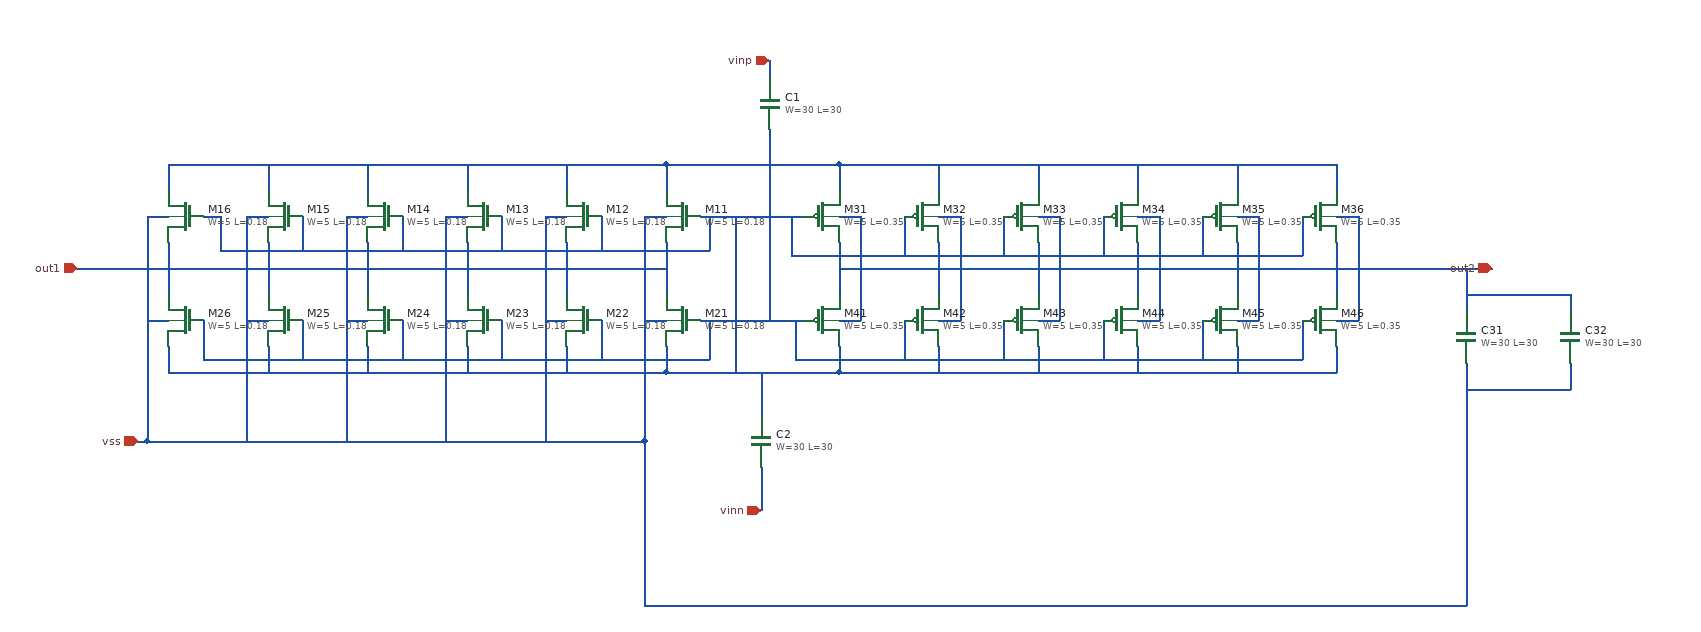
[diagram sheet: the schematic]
v {xschem version=3.1.0 file_version=1.2
}
G {}
K {}
V {}
S {}
E {}
N 765 -280 965 -280 { lab=#net1}
N 765 -520 765 -490 { lab=#net2}
N 765 -520 965 -520 { lab=#net2}
N 845 -460 845 -280 { lab=#net1}
N 885 -520 885 -340 { lab=#net2}
N 965 -520 965 -490 { lab=#net2}
N 965 -430 965 -370 { lab=out2}
N 965 -310 965 -280 { lab=#net1}
N 765 -310 765 -280 { lab=#net1}
N 805 -340 925 -340 { lab=#net2}
N 805 -460 925 -460 { lab=#net1}
N 765 -430 765 -370 { lab=vss}
N 885 -560 885 -520 {
lab=#net2}
N 875 -280 875 -230 {
lab=#net1}
N 885 -640 885 -620 {
lab=vinp}
N 875 -170 875 -120 {
lab=vinn}
N 190 -520 190 -490 {
lab=#net2}
N 190 -520 765 -520 {
lab=#net2}
N 305 -520 305 -490 {
lab=#net2}
N 420 -520 420 -490 {
lab=#net2}
N 535 -520 535 -490 {
lab=#net2}
N 650 -520 650 -490 {
lab=#net2}
N 965 -520 1540 -520 {
lab=#net2}
N 1540 -520 1540 -490 {
lab=#net2}
N 1080 -520 1080 -490 {
lab=#net2}
N 1195 -520 1195 -490 {
lab=#net2}
N 1310 -520 1310 -490 {
lab=#net2}
N 1425 -520 1425 -490 {
lab=#net2}
N 190 -280 765 -280 {
lab=#net1}
N 190 -310 190 -280 {
lab=#net1}
N 305 -310 305 -280 {
lab=#net1}
N 420 -310 420 -280 {
lab=#net1}
N 535 -310 535 -280 {
lab=#net1}
N 650 -310 650 -280 {
lab=#net1}
N 965 -280 1540 -280 {
lab=#net1}
N 1540 -310 1540 -280 {
lab=#net1}
N 1425 -310 1425 -280 {
lab=#net1}
N 1310 -310 1310 -280 {
lab=#net1}
N 1195 -310 1195 -280 {
lab=#net1}
N 1080 -310 1080 -280 {
lab=#net1}
N 190 -430 190 -370 {
lab=vss}
N 305 -430 305 -370 {
lab=vss}
N 420 -430 420 -370 {
lab=vss}
N 535 -430 535 -370 {
lab=vss}
N 650 -430 650 -370 {
lab=vss}
N 650 -400 765 -400 {
lab=vss}
N 535 -400 650 -400 {
lab=vss}
N 420 -400 535 -400 {
lab=vss}
N 305 -400 420 -400 {
lab=vss}
N 190 -400 305 -400 {
lab=vss}
N 1540 -430 1540 -370 {
lab=out2}
N 1080 -430 1080 -370 {
lab=out2}
N 1195 -430 1195 -370 {
lab=out2}
N 1310 -430 1310 -370 {
lab=out2}
N 1425 -430 1425 -370 {
lab=out2}
N 965 -400 1080 -400 {
lab=out2}
N 1080 -400 1195 -400 {
lab=out2}
N 1195 -400 1310 -400 {
lab=out2}
N 1310 -400 1425 -400 {
lab=out2}
N 1425 -400 1540 -400 {
lab=out2}
N 230 -460 250 -460 {
lab=#net1}
N 250 -460 250 -420 {
lab=#net1}
N 250 -420 815 -420 {
lab=#net1}
N 815 -460 815 -420 {
lab=#net1}
N 345 -460 345 -420 {
lab=#net1}
N 460 -460 460 -420 {
lab=#net1}
N 575 -460 575 -420 {
lab=#net1}
N 690 -460 690 -420 {
lab=#net1}
N 230 -340 230 -295 {
lab=#net2}
N 230 -295 815 -295 {
lab=#net2}
N 815 -340 815 -295 {
lab=#net2}
N 690 -340 690 -295 {
lab=#net2}
N 575 -340 575 -295 {
lab=#net2}
N 460 -340 460 -295 {
lab=#net2}
N 345 -340 345 -295 {
lab=#net2}
N 1500 -460 1500 -415 {
lab=#net1}
N 910 -415 1500 -415 {
lab=#net1}
N 910 -460 910 -415 {
lab=#net1}
N 1040 -460 1040 -415 {
lab=#net1}
N 1155 -460 1155 -415 {
lab=#net1}
N 1270 -460 1270 -415 {
lab=#net1}
N 1385 -460 1385 -415 {
lab=#net1}
N 1500 -340 1500 -295 {
lab=#net2}
N 915 -295 1500 -295 {
lab=#net2}
N 915 -340 915 -295 {
lab=#net2}
N 1040 -340 1040 -295 {
lab=#net2}
N 1155 -340 1155 -295 {
lab=#net2}
N 1270 -340 1270 -295 {
lab=#net2}
N 1385 -340 1385 -295 {
lab=#net2}
N 165 -460 190 -460 {
lab=vss}
N 165 -460 165 -200 {
lab=vss}
N 155 -200 165 -200 {
lab=vss}
N 165 -340 190 -340 {
lab=vss}
N 165 -200 740 -200 {
lab=vss}
N 740 -460 740 -200 {
lab=vss}
N 740 -460 765 -460 {
lab=vss}
N 740 -340 765 -340 {
lab=vss}
N 625 -460 650 -460 {
lab=vss}
N 625 -340 650 -340 {
lab=vss}
N 510 -340 535 -340 {
lab=vss}
N 510 -460 535 -460 {
lab=vss}
N 395 -460 420 -460 {
lab=vss}
N 395 -340 420 -340 {
lab=vss}
N 280 -340 305 -340 {
lab=vss}
N 280 -460 305 -460 {
lab=vss}
N 280 -460 280 -200 {
lab=vss}
N 395 -460 395 -200 {
lab=vss}
N 510 -460 510 -200 {
lab=vss}
N 625 -460 625 -200 {
lab=vss}
N 965 -460 990 -460 {
lab=out2}
N 965 -340 990 -340 {
lab=out2}
N 990 -400 990 -340 {
lab=out2}
N 990 -460 990 -400 {
lab=out2}
N 1080 -460 1105 -460 {
lab=out2}
N 1080 -340 1105 -340 {
lab=out2}
N 1195 -340 1220 -340 {
lab=out2}
N 1195 -460 1220 -460 {
lab=out2}
N 1310 -460 1335 -460 {
lab=out2}
N 1310 -340 1335 -340 {
lab=out2}
N 1425 -340 1450 -340 {
lab=out2}
N 1425 -460 1450 -460 {
lab=out2}
N 1540 -460 1565 -460 {
lab=out2}
N 1540 -340 1565 -340 {
lab=out2}
N 1105 -400 1105 -340 {
lab=out2}
N 1105 -460 1105 -400 {
lab=out2}
N 1220 -460 1220 -400 {
lab=out2}
N 1220 -400 1220 -340 {
lab=out2}
N 1335 -400 1335 -340 {
lab=out2}
N 1335 -460 1335 -400 {
lab=out2}
N 1450 -460 1450 -400 {
lab=out2}
N 1450 -400 1450 -340 {
lab=out2}
N 1565 -460 1565 -400 {
lab=out2}
N 1565 -400 1565 -340 {
lab=out2}
N 740 -200 740 -10 {
lab=vss}
N 740 -10 1690 -10 {
lab=vss}
N 1690 -290 1690 -10 {
lab=vss}
N 1690 -400 1690 -350 {
lab=out2}
N 1540 -400 1720 -400 {
lab=out2}
N 1810 -370 1810 -350 {
lab=out2}
N 1690 -370 1810 -370 {
lab=out2}
N 1810 -290 1810 -260 {
lab=vss}
N 1690 -260 1810 -260 {
lab=vss}
N 85 -400 190 -400 {
lab=vss}
C {sky130_fd_pr/cap_mim_m3_1.sym} 885 -590 0 0 {name=C1 model=cap_mim_m3_1 W=30 L=30 MF=1 spiceprefix=X}
C {sky130_fd_pr/cap_mim_m3_1.sym} 875 -200 0 0 {name=C2 model=cap_mim_m3_1 W=30 L=30 MF=1 spiceprefix=X}
C {sky130_fd_pr/nfet_01v8_lvt.sym} 785 -460 0 1 {name=M11
L=0.18
W=5
nf=1
mult=1
ad="'int((nf+1)/2) * W/nf * 0.29'" 
pd="'2*int((nf+1)/2) * (W/nf + 0.29)'"
as="'int((nf+2)/2) * W/nf * 0.29'" 
ps="'2*int((nf+2)/2) * (W/nf + 0.29)'"
nrd="'0.29 / W'" nrs="'0.29 / W'"
sa=0 sb=0 sd=0
model=nfet_01v8_lvt
spiceprefix=X
}
C {sky130_fd_pr/nfet_01v8_lvt.sym} 785 -340 2 0 {name=M21
L=0.18
W=5
nf=1
mult=1
ad="'int((nf+1)/2) * W/nf * 0.29'" 
pd="'2*int((nf+1)/2) * (W/nf + 0.29)'"
as="'int((nf+2)/2) * W/nf * 0.29'" 
ps="'2*int((nf+2)/2) * (W/nf + 0.29)'"
nrd="'0.29 / W'" nrs="'0.29 / W'"
sa=0 sb=0 sd=0
model=nfet_01v8_lvt
spiceprefix=X
}
C {sky130_fd_pr/pfet_01v8_lvt.sym} 945 -460 2 1 {name=M31
L=0.35
W=5
nf=1
mult=1
ad="'int((nf+1)/2) * W/nf * 0.29'" 
pd="'2*int((nf+1)/2) * (W/nf + 0.29)'"
as="'int((nf+2)/2) * W/nf * 0.29'" 
ps="'2*int((nf+2)/2) * (W/nf + 0.29)'"
nrd="'0.29 / W'" nrs="'0.29 / W'"
sa=0 sb=0 sd=0
model=pfet_01v8_lvt
spiceprefix=X
}
C {sky130_fd_pr/pfet_01v8_lvt.sym} 945 -340 0 0 {name=M41
L=0.35
W=5
nf=1
mult=1
ad="'int((nf+1)/2) * W/nf * 0.29'" 
pd="'2*int((nf+1)/2) * (W/nf + 0.29)'"
as="'int((nf+2)/2) * W/nf * 0.29'" 
ps="'2*int((nf+2)/2) * (W/nf + 0.29)'"
nrd="'0.29 / W'" nrs="'0.29 / W'"
sa=0 sb=0 sd=0
model=pfet_01v8_lvt
spiceprefix=X
}
C {sky130_fd_pr/nfet_01v8_lvt.sym} 670 -460 0 1 {name=M12
L=0.18
W=5
nf=1
mult=1
ad="'int((nf+1)/2) * W/nf * 0.29'" 
pd="'2*int((nf+1)/2) * (W/nf + 0.29)'"
as="'int((nf+2)/2) * W/nf * 0.29'" 
ps="'2*int((nf+2)/2) * (W/nf + 0.29)'"
nrd="'0.29 / W'" nrs="'0.29 / W'"
sa=0 sb=0 sd=0
model=nfet_01v8_lvt
spiceprefix=X
}
C {sky130_fd_pr/nfet_01v8_lvt.sym} 555 -460 0 1 {name=M13
L=0.18
W=5
nf=1
mult=1
ad="'int((nf+1)/2) * W/nf * 0.29'" 
pd="'2*int((nf+1)/2) * (W/nf + 0.29)'"
as="'int((nf+2)/2) * W/nf * 0.29'" 
ps="'2*int((nf+2)/2) * (W/nf + 0.29)'"
nrd="'0.29 / W'" nrs="'0.29 / W'"
sa=0 sb=0 sd=0
model=nfet_01v8_lvt
spiceprefix=X
}
C {sky130_fd_pr/nfet_01v8_lvt.sym} 440 -460 0 1 {name=M14
L=0.18
W=5
nf=1
mult=1
ad="'int((nf+1)/2) * W/nf * 0.29'" 
pd="'2*int((nf+1)/2) * (W/nf + 0.29)'"
as="'int((nf+2)/2) * W/nf * 0.29'" 
ps="'2*int((nf+2)/2) * (W/nf + 0.29)'"
nrd="'0.29 / W'" nrs="'0.29 / W'"
sa=0 sb=0 sd=0
model=nfet_01v8_lvt
spiceprefix=X
}
C {sky130_fd_pr/nfet_01v8_lvt.sym} 325 -460 0 1 {name=M15
L=0.18
W=5
nf=1
mult=1
ad="'int((nf+1)/2) * W/nf * 0.29'" 
pd="'2*int((nf+1)/2) * (W/nf + 0.29)'"
as="'int((nf+2)/2) * W/nf * 0.29'" 
ps="'2*int((nf+2)/2) * (W/nf + 0.29)'"
nrd="'0.29 / W'" nrs="'0.29 / W'"
sa=0 sb=0 sd=0
model=nfet_01v8_lvt
spiceprefix=X
}
C {sky130_fd_pr/nfet_01v8_lvt.sym} 210 -460 0 1 {name=M16
L=0.18
W=5
nf=1
mult=1
ad="'int((nf+1)/2) * W/nf * 0.29'" 
pd="'2*int((nf+1)/2) * (W/nf + 0.29)'"
as="'int((nf+2)/2) * W/nf * 0.29'" 
ps="'2*int((nf+2)/2) * (W/nf + 0.29)'"
nrd="'0.29 / W'" nrs="'0.29 / W'"
sa=0 sb=0 sd=0
model=nfet_01v8_lvt
spiceprefix=X
}
C {sky130_fd_pr/nfet_01v8_lvt.sym} 670 -340 2 0 {name=M22
L=0.18
W=5
nf=1
mult=1
ad="'int((nf+1)/2) * W/nf * 0.29'" 
pd="'2*int((nf+1)/2) * (W/nf + 0.29)'"
as="'int((nf+2)/2) * W/nf * 0.29'" 
ps="'2*int((nf+2)/2) * (W/nf + 0.29)'"
nrd="'0.29 / W'" nrs="'0.29 / W'"
sa=0 sb=0 sd=0
model=nfet_01v8_lvt
spiceprefix=X
}
C {sky130_fd_pr/nfet_01v8_lvt.sym} 555 -340 2 0 {name=M23
L=0.18
W=5
nf=1
mult=1
ad="'int((nf+1)/2) * W/nf * 0.29'" 
pd="'2*int((nf+1)/2) * (W/nf + 0.29)'"
as="'int((nf+2)/2) * W/nf * 0.29'" 
ps="'2*int((nf+2)/2) * (W/nf + 0.29)'"
nrd="'0.29 / W'" nrs="'0.29 / W'"
sa=0 sb=0 sd=0
model=nfet_01v8_lvt
spiceprefix=X
}
C {sky130_fd_pr/nfet_01v8_lvt.sym} 440 -340 2 0 {name=M24
L=0.18
W=5
nf=1
mult=1
ad="'int((nf+1)/2) * W/nf * 0.29'" 
pd="'2*int((nf+1)/2) * (W/nf + 0.29)'"
as="'int((nf+2)/2) * W/nf * 0.29'" 
ps="'2*int((nf+2)/2) * (W/nf + 0.29)'"
nrd="'0.29 / W'" nrs="'0.29 / W'"
sa=0 sb=0 sd=0
model=nfet_01v8_lvt
spiceprefix=X
}
C {sky130_fd_pr/nfet_01v8_lvt.sym} 325 -340 2 0 {name=M25
L=0.18
W=5
nf=1
mult=1
ad="'int((nf+1)/2) * W/nf * 0.29'" 
pd="'2*int((nf+1)/2) * (W/nf + 0.29)'"
as="'int((nf+2)/2) * W/nf * 0.29'" 
ps="'2*int((nf+2)/2) * (W/nf + 0.29)'"
nrd="'0.29 / W'" nrs="'0.29 / W'"
sa=0 sb=0 sd=0
model=nfet_01v8_lvt
spiceprefix=X
}
C {sky130_fd_pr/nfet_01v8_lvt.sym} 210 -340 2 0 {name=M26
L=0.18
W=5
nf=1
mult=1
ad="'int((nf+1)/2) * W/nf * 0.29'" 
pd="'2*int((nf+1)/2) * (W/nf + 0.29)'"
as="'int((nf+2)/2) * W/nf * 0.29'" 
ps="'2*int((nf+2)/2) * (W/nf + 0.29)'"
nrd="'0.29 / W'" nrs="'0.29 / W'"
sa=0 sb=0 sd=0
model=nfet_01v8_lvt
spiceprefix=X
}
C {sky130_fd_pr/pfet_01v8_lvt.sym} 1060 -460 2 1 {name=M32
L=0.35
W=5
nf=1
mult=1
ad="'int((nf+1)/2) * W/nf * 0.29'" 
pd="'2*int((nf+1)/2) * (W/nf + 0.29)'"
as="'int((nf+2)/2) * W/nf * 0.29'" 
ps="'2*int((nf+2)/2) * (W/nf + 0.29)'"
nrd="'0.29 / W'" nrs="'0.29 / W'"
sa=0 sb=0 sd=0
model=pfet_01v8_lvt
spiceprefix=X
}
C {sky130_fd_pr/pfet_01v8_lvt.sym} 1175 -460 2 1 {name=M33
L=0.35
W=5
nf=1
mult=1
ad="'int((nf+1)/2) * W/nf * 0.29'" 
pd="'2*int((nf+1)/2) * (W/nf + 0.29)'"
as="'int((nf+2)/2) * W/nf * 0.29'" 
ps="'2*int((nf+2)/2) * (W/nf + 0.29)'"
nrd="'0.29 / W'" nrs="'0.29 / W'"
sa=0 sb=0 sd=0
model=pfet_01v8_lvt
spiceprefix=X
}
C {sky130_fd_pr/pfet_01v8_lvt.sym} 1290 -460 2 1 {name=M34
L=0.35
W=5
nf=1
mult=1
ad="'int((nf+1)/2) * W/nf * 0.29'" 
pd="'2*int((nf+1)/2) * (W/nf + 0.29)'"
as="'int((nf+2)/2) * W/nf * 0.29'" 
ps="'2*int((nf+2)/2) * (W/nf + 0.29)'"
nrd="'0.29 / W'" nrs="'0.29 / W'"
sa=0 sb=0 sd=0
model=pfet_01v8_lvt
spiceprefix=X
}
C {sky130_fd_pr/pfet_01v8_lvt.sym} 1405 -460 2 1 {name=M35
L=0.35
W=5
nf=1
mult=1
ad="'int((nf+1)/2) * W/nf * 0.29'" 
pd="'2*int((nf+1)/2) * (W/nf + 0.29)'"
as="'int((nf+2)/2) * W/nf * 0.29'" 
ps="'2*int((nf+2)/2) * (W/nf + 0.29)'"
nrd="'0.29 / W'" nrs="'0.29 / W'"
sa=0 sb=0 sd=0
model=pfet_01v8_lvt
spiceprefix=X
}
C {sky130_fd_pr/pfet_01v8_lvt.sym} 1520 -460 2 1 {name=M36
L=0.35
W=5
nf=1
mult=1
ad="'int((nf+1)/2) * W/nf * 0.29'" 
pd="'2*int((nf+1)/2) * (W/nf + 0.29)'"
as="'int((nf+2)/2) * W/nf * 0.29'" 
ps="'2*int((nf+2)/2) * (W/nf + 0.29)'"
nrd="'0.29 / W'" nrs="'0.29 / W'"
sa=0 sb=0 sd=0
model=pfet_01v8_lvt
spiceprefix=X
}
C {sky130_fd_pr/pfet_01v8_lvt.sym} 1060 -340 0 0 {name=M42
L=0.35
W=5
nf=1
mult=1
ad="'int((nf+1)/2) * W/nf * 0.29'" 
pd="'2*int((nf+1)/2) * (W/nf + 0.29)'"
as="'int((nf+2)/2) * W/nf * 0.29'" 
ps="'2*int((nf+2)/2) * (W/nf + 0.29)'"
nrd="'0.29 / W'" nrs="'0.29 / W'"
sa=0 sb=0 sd=0
model=pfet_01v8_lvt
spiceprefix=X
}
C {sky130_fd_pr/pfet_01v8_lvt.sym} 1175 -340 0 0 {name=M43
L=0.35
W=5
nf=1
mult=1
ad="'int((nf+1)/2) * W/nf * 0.29'" 
pd="'2*int((nf+1)/2) * (W/nf + 0.29)'"
as="'int((nf+2)/2) * W/nf * 0.29'" 
ps="'2*int((nf+2)/2) * (W/nf + 0.29)'"
nrd="'0.29 / W'" nrs="'0.29 / W'"
sa=0 sb=0 sd=0
model=pfet_01v8_lvt
spiceprefix=X
}
C {sky130_fd_pr/pfet_01v8_lvt.sym} 1290 -340 0 0 {name=M44
L=0.35
W=5
nf=1
mult=1
ad="'int((nf+1)/2) * W/nf * 0.29'" 
pd="'2*int((nf+1)/2) * (W/nf + 0.29)'"
as="'int((nf+2)/2) * W/nf * 0.29'" 
ps="'2*int((nf+2)/2) * (W/nf + 0.29)'"
nrd="'0.29 / W'" nrs="'0.29 / W'"
sa=0 sb=0 sd=0
model=pfet_01v8_lvt
spiceprefix=X
}
C {sky130_fd_pr/pfet_01v8_lvt.sym} 1405 -340 0 0 {name=M45
L=0.35
W=5
nf=1
mult=1
ad="'int((nf+1)/2) * W/nf * 0.29'" 
pd="'2*int((nf+1)/2) * (W/nf + 0.29)'"
as="'int((nf+2)/2) * W/nf * 0.29'" 
ps="'2*int((nf+2)/2) * (W/nf + 0.29)'"
nrd="'0.29 / W'" nrs="'0.29 / W'"
sa=0 sb=0 sd=0
model=pfet_01v8_lvt
spiceprefix=X
}
C {sky130_fd_pr/pfet_01v8_lvt.sym} 1520 -340 0 0 {name=M46
L=0.35
W=5
nf=1
mult=1
ad="'int((nf+1)/2) * W/nf * 0.29'" 
pd="'2*int((nf+1)/2) * (W/nf + 0.29)'"
as="'int((nf+2)/2) * W/nf * 0.29'" 
ps="'2*int((nf+2)/2) * (W/nf + 0.29)'"
nrd="'0.29 / W'" nrs="'0.29 / W'"
sa=0 sb=0 sd=0
model=pfet_01v8_lvt
spiceprefix=X
}
C {devices/iopin.sym} 885 -640 3 0 {name=p2 lab=vinp}
C {devices/iopin.sym} 875 -120 1 0 {name=p3 lab=vinn}
C {devices/iopin.sym} 155 -200 2 0 {name=p4 lab=vss}
C {devices/iopin.sym} 1720 -400 0 0 {name=p6 lab=out2}
C {sky130_fd_pr/cap_mim_m3_1.sym} 1690 -320 0 0 {name=C31 model=cap_mim_m3_1 W=30 L=30 MF=1 spiceprefix=X}
C {sky130_fd_pr/cap_mim_m3_1.sym} 1810 -320 0 0 {name=C32 model=cap_mim_m3_1 W=30 L=30 MF=1 spiceprefix=X}
C {devices/iopin.sym} 85 -400 2 0 {name=p1 lab=out1}
